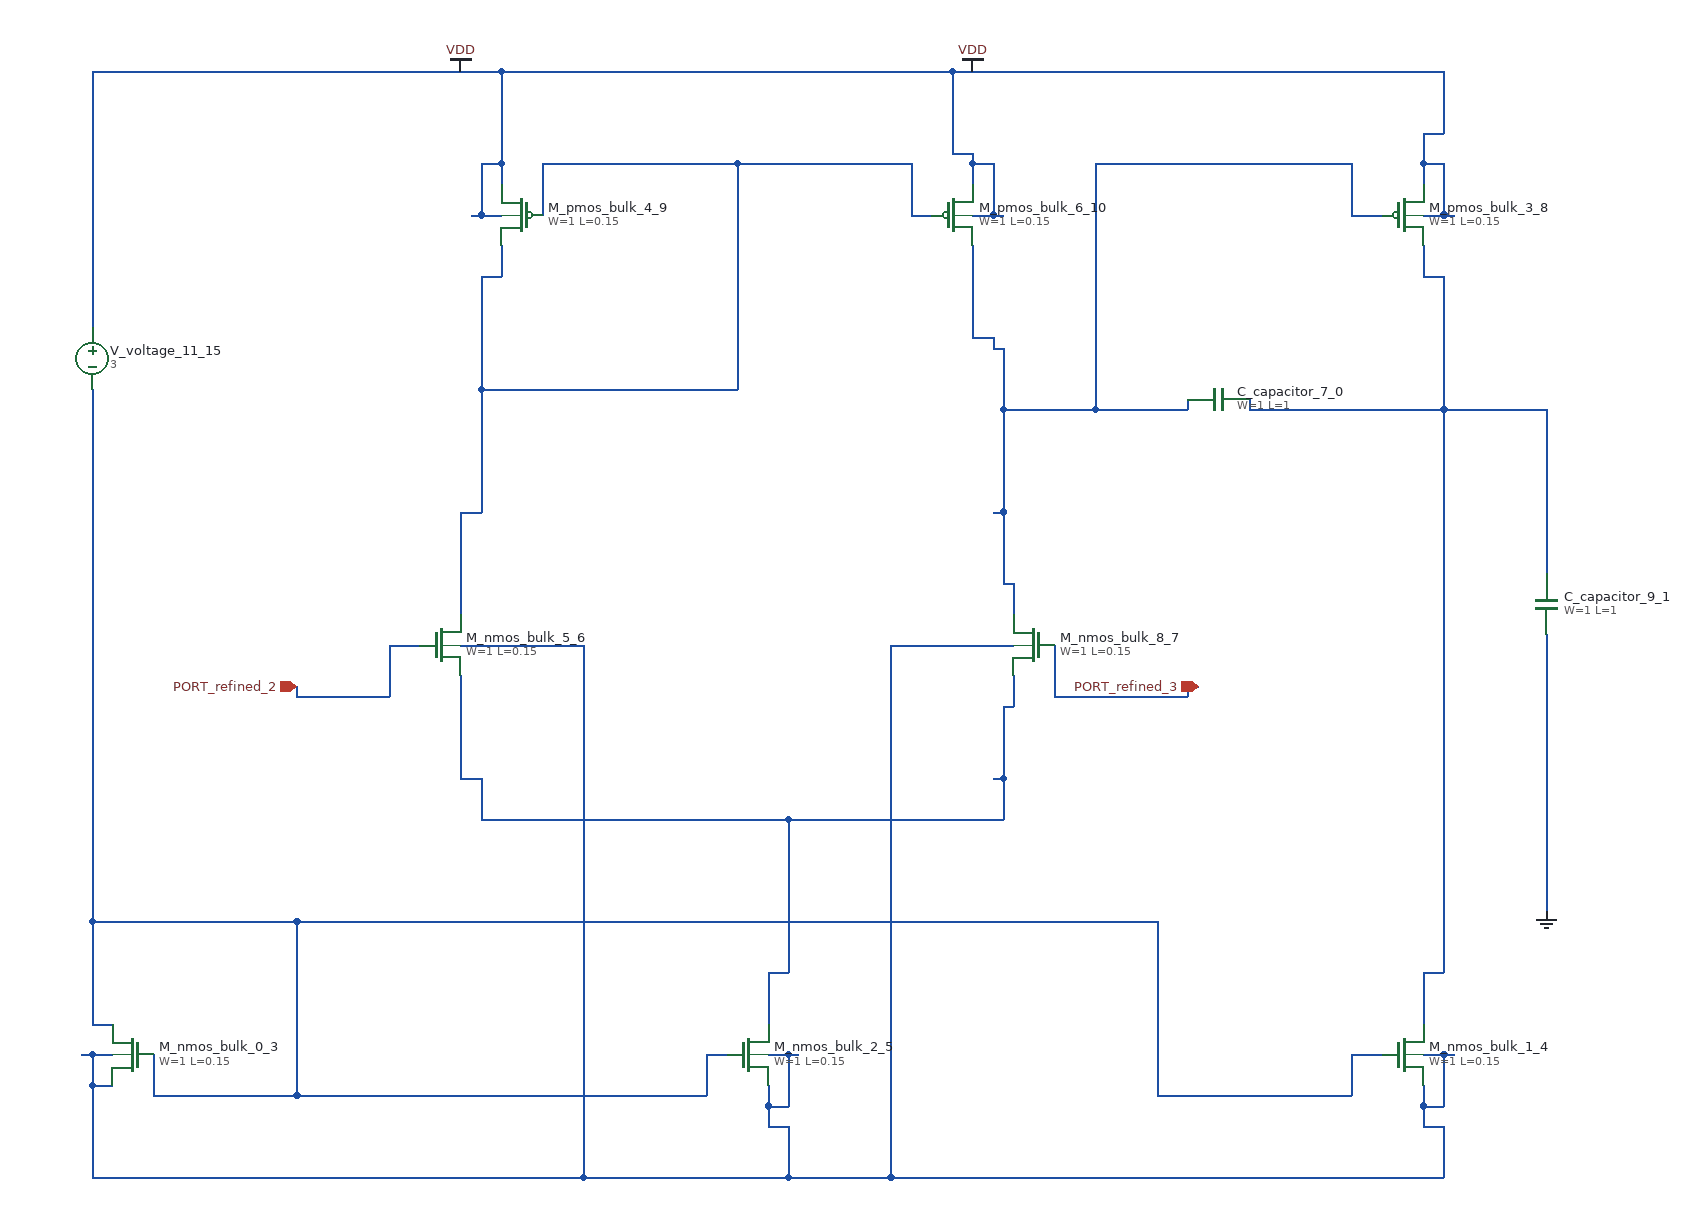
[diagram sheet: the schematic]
v {xschem version=3.4.8 file_version=1.2}
G {}
K {}
V {}
S {}
E {}
C {sky130_fd_pr/cap_mim_m3_1.sym} 1180 480 3 0 {name="C_capacitor_7_0" model=cap_mim_m3_1 W=1 L=1 MF=1 spiceprefix=X}
C {sky130_fd_pr/cap_mim_m3_1.sym} 1500 680 2 0 {name="C_capacitor_9_1" model=cap_mim_m3_1 W=1 L=1 MF=1 spiceprefix=X}
C {devices/gnd.sym} 1500 980 0 0 {name="l_gnd_10_2" lab="GND"}
C {sky130_fd_pr/nfet_01v8.sym} 120 1120 0 1 {name="M_nmos_bulk_0_3"
W=1
L=0.15
nf=1 
mult=1
ad="expr('int((@nf + 1)/2) * @W / @nf * 0.29')"
pd="expr('2*int((@nf + 1)/2) * (@W / @nf + 0.29)')"
as="expr('int((@nf + 2)/2) * @W / @nf * 0.29')"
ps="expr('2*int((@nf + 2)/2) * (@W / @nf + 0.29)')"
nrd="expr('0.29 / @W ')" nrs="expr('0.29 / @W ')"
sa=0 sb=0 sd=0
model=nfet_01v8
spiceprefix=X
}
C {sky130_fd_pr/nfet_01v8.sym} 1360 1120 0 0 {name="M_nmos_bulk_1_4"
W=1
L=0.15
nf=1 
mult=1
ad="expr('int((@nf + 1)/2) * @W / @nf * 0.29')"
pd="expr('2*int((@nf + 1)/2) * (@W / @nf + 0.29)')"
as="expr('int((@nf + 2)/2) * @W / @nf * 0.29')"
ps="expr('2*int((@nf + 2)/2) * (@W / @nf + 0.29)')"
nrd="expr('0.29 / @W ')" nrs="expr('0.29 / @W ')"
sa=0 sb=0 sd=0
model=nfet_01v8
spiceprefix=X
}
C {sky130_fd_pr/nfet_01v8.sym} 720 1120 0 0 {name="M_nmos_bulk_2_5"
W=1
L=0.15
nf=1 
mult=1
ad="expr('int((@nf + 1)/2) * @W / @nf * 0.29')"
pd="expr('2*int((@nf + 1)/2) * (@W / @nf + 0.29)')"
as="expr('int((@nf + 2)/2) * @W / @nf * 0.29')"
ps="expr('2*int((@nf + 2)/2) * (@W / @nf + 0.29)')"
nrd="expr('0.29 / @W ')" nrs="expr('0.29 / @W ')"
sa=0 sb=0 sd=0
model=nfet_01v8
spiceprefix=X
}
C {sky130_fd_pr/nfet_01v8.sym} 420 720 0 0 {name="M_nmos_bulk_5_6"
W=1
L=0.15
nf=1 
mult=1
ad="expr('int((@nf + 1)/2) * @W / @nf * 0.29')"
pd="expr('2*int((@nf + 1)/2) * (@W / @nf + 0.29)')"
as="expr('int((@nf + 2)/2) * @W / @nf * 0.29')"
ps="expr('2*int((@nf + 2)/2) * (@W / @nf + 0.29)')"
nrd="expr('0.29 / @W ')" nrs="expr('0.29 / @W ')"
sa=0 sb=0 sd=0
model=nfet_01v8
spiceprefix=X
}
C {sky130_fd_pr/nfet_01v8.sym} 1000 720 0 1 {name="M_nmos_bulk_8_7"
W=1
L=0.15
nf=1 
mult=1
ad="expr('int((@nf + 1)/2) * @W / @nf * 0.29')"
pd="expr('2*int((@nf + 1)/2) * (@W / @nf + 0.29)')"
as="expr('int((@nf + 2)/2) * @W / @nf * 0.29')"
ps="expr('2*int((@nf + 2)/2) * (@W / @nf + 0.29)')"
nrd="expr('0.29 / @W ')" nrs="expr('0.29 / @W ')"
sa=0 sb=0 sd=0
model=nfet_01v8
spiceprefix=X
}
C {sky130_fd_pr/pfet_01v8.sym} 1360 300 0 0 {name="M_pmos_bulk_3_8"
W=1
L=0.15
nf=1
mult=1
ad="expr('int((@nf + 1)/2) * @W / @nf * 0.29')"
pd="expr('2*int((@nf + 1)/2) * (@W / @nf + 0.29)')"
as="expr('int((@nf + 2)/2) * @W / @nf * 0.29')"
ps="expr('2*int((@nf + 2)/2) * (@W / @nf + 0.29)')"
nrd="expr('0.29 / @W ')" nrs="expr('0.29 / @W ')"
sa=0 sb=0 sd=0
model=pfet_01v8
spiceprefix=X
}
C {sky130_fd_pr/pfet_01v8.sym} 500 300 0 1 {name="M_pmos_bulk_4_9"
W=1
L=0.15
nf=1
mult=1
ad="expr('int((@nf + 1)/2) * @W / @nf * 0.29')"
pd="expr('2*int((@nf + 1)/2) * (@W / @nf + 0.29)')"
as="expr('int((@nf + 2)/2) * @W / @nf * 0.29')"
ps="expr('2*int((@nf + 2)/2) * (@W / @nf + 0.29)')"
nrd="expr('0.29 / @W ')" nrs="expr('0.29 / @W ')"
sa=0 sb=0 sd=0
model=pfet_01v8
spiceprefix=X
}
C {sky130_fd_pr/pfet_01v8.sym} 920 300 0 0 {name="M_pmos_bulk_6_10"
W=1
L=0.15
nf=1
mult=1
ad="expr('int((@nf + 1)/2) * @W / @nf * 0.29')"
pd="expr('2*int((@nf + 1)/2) * (@W / @nf + 0.29)')"
as="expr('int((@nf + 2)/2) * @W / @nf * 0.29')"
ps="expr('2*int((@nf + 2)/2) * (@W / @nf + 0.29)')"
nrd="expr('0.29 / @W ')" nrs="expr('0.29 / @W ')"
sa=0 sb=0 sd=0
model=pfet_01v8
spiceprefix=X
}
C {devices/ipin.sym} 280 760 0 0 {name="p_port_12_11" lab="PORT_refined_2"}
C {devices/ipin.sym} 1160 760 0 0 {name="p_port_13_12" lab="PORT_refined_3"}
C {devices/vdd.sym} 940 160 0 0 {name="l_vdd_18_13" lab="VDD"}
C {devices/vdd.sym} 440 160 0 0 {name="l_vdd_19_14" lab="VDD"}
C {devices/vsource.sym} 80 440 0 0 {name="V_voltage_11_15" value=3 savecurrent=false}
N 80 1240 560 1240 {}
N 560 1240 760 1240 {}
N 760 1240 860 1240 {}
N 860 1240 1400 1240 {}
N 740 1190 760 1190 {}
N 1380 1190 1400 1190 {}
N 740 1170 760 1170 {}
N 1380 1170 1400 1170 {}
N 80 1150 100 1150 {}
N 70 1120 80 1120 {}
N 80 1120 100 1120 {}
N 740 1120 760 1120 {}
N 760 1120 770 1120 {}
N 1380 1120 1400 1120 {}
N 1400 1120 1410 1120 {}
N 440 720 560 720 {}
N 860 720 980 720 {}
N 80 1240 80 1150 {}
N 80 1150 80 1120 {}
N 560 1240 560 720 {}
N 740 1190 740 1170 {}
N 740 1170 740 1150 {}
N 760 1240 760 1190 {}
N 760 1170 760 1120 {}
N 860 1240 860 720 {}
N 1380 1190 1380 1170 {}
N 1380 1170 1380 1150 {}
N 1400 1240 1400 1190 {}
N 1400 1170 1400 1120 {}
N 140 1160 280 1160 {}
N 280 1160 680 1160 {}
N 1120 1160 1310 1160 {}
N 680 1120 700 1120 {}
N 1310 1120 1340 1120 {}
N 80 1090 100 1090 {}
N 80 990 280 990 {}
N 280 990 1120 990 {}
N 80 1090 80 990 {}
N 80 990 80 470 {}
N 140 1160 140 1120 {}
N 280 1160 280 990 {}
N 680 1160 680 1120 {}
N 1120 1160 1120 990 {}
N 1310 1160 1310 1120 {}
N 280 770 370 770 {}
N 370 720 400 720 {}
N 280 770 280 760 {}
N 370 770 370 720 {}
N 1020 770 1150 770 {}
N 1150 760 1160 760 {}
N 1020 770 1020 720 {}
N 1150 770 1150 760 {}
N 450 300 460 300 {}
N 460 300 480 300 {}
N 940 300 960 300 {}
N 960 300 970 300 {}
N 1380 300 1400 300 {}
N 1400 300 1410 300 {}
N 460 250 480 250 {}
N 940 250 960 250 {}
N 1380 250 1400 250 {}
N 920 240 940 240 {}
N 1380 220 1400 220 {}
N 80 160 440 160 {}
N 440 160 480 160 {}
N 480 160 920 160 {}
N 920 160 940 160 {}
N 940 160 1400 160 {}
N 80 410 80 160 {}
N 460 300 460 250 {}
N 480 270 480 250 {}
N 480 250 480 160 {}
N 920 240 920 160 {}
N 940 270 940 250 {}
N 940 250 940 240 {}
N 960 300 960 250 {}
N 1380 270 1380 250 {}
N 1380 250 1380 220 {}
N 1400 300 1400 250 {}
N 1400 220 1400 160 {}
N 740 1040 760 1040 {}
N 460 890 760 890 {}
N 760 890 970 890 {}
N 440 850 460 850 {}
N 960 850 970 850 {}
N 970 780 980 780 {}
N 440 850 440 750 {}
N 460 890 460 850 {}
N 740 1090 740 1040 {}
N 760 1040 760 890 {}
N 970 890 970 850 {}
N 970 850 970 780 {}
N 980 780 980 750 {}
N 440 590 460 590 {}
N 460 470 710 470 {}
N 460 360 480 360 {}
N 880 300 900 300 {}
N 520 250 710 250 {}
N 710 250 880 250 {}
N 440 690 440 590 {}
N 460 590 460 470 {}
N 460 470 460 360 {}
N 480 360 480 330 {}
N 520 300 520 250 {}
N 710 470 710 250 {}
N 880 300 880 250 {}
N 970 660 980 660 {}
N 960 590 970 590 {}
N 970 490 1060 490 {}
N 1060 490 1150 490 {}
N 960 430 970 430 {}
N 940 420 960 420 {}
N 1310 300 1340 300 {}
N 1060 250 1310 250 {}
N 940 420 940 330 {}
N 960 430 960 420 {}
N 970 660 970 590 {}
N 970 590 970 490 {}
N 970 490 970 430 {}
N 980 690 980 660 {}
N 1060 490 1060 250 {}
N 1150 490 1150 480 {}
N 1310 300 1310 250 {}
N 1380 1040 1400 1040 {}
N 1210 490 1400 490 {}
N 1400 490 1500 490 {}
N 1380 360 1400 360 {}
N 1210 490 1210 480 {}
N 1380 1090 1380 1040 {}
N 1380 360 1380 330 {}
N 1400 1040 1400 490 {}
N 1400 490 1400 360 {}
N 1500 650 1500 490 {}
N 1500 980 1500 710 {}
